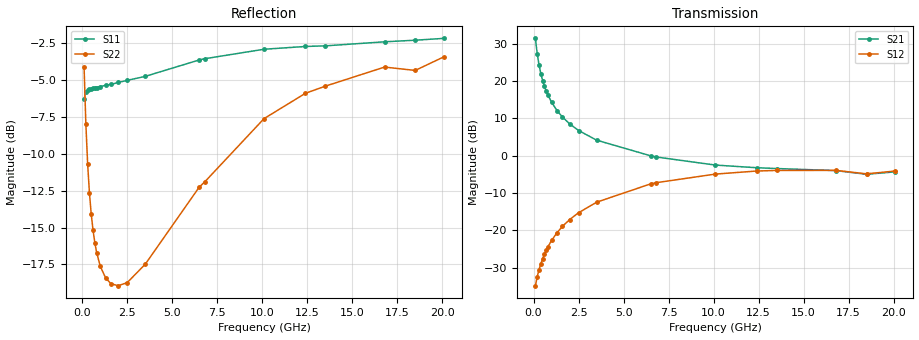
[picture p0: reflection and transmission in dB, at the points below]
!  Infineon Technologies AG
! BFR380L3 , PF131585-7, No.6, Th 09.10.01, soldered on pcb-board, measured with PP GSG850
!  Vce=5.0 V,  Ic=75.0 mA
! Common Emitter S-Parameters:  15. November 2001
#  GHz  S  MA  R  50
! f  S11  S21  S12  S22
! GHz  Mag  Ang  Mag  Ang  Mag  Ang  Mag  Ang
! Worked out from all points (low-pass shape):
!   201 points, 100 MHz to 20.1 GHz, reference 50 ohm
!   highest |S21| = 31.42 dB at 100 MHz (marker M1); lowest = -5.0 dB at 18.5 GHz (marker M2)
!   |S21| within 3 dB of the highest: start of sweep to 173.1 MHz
!   lowest |S11| = -6.3 dB at 100 MHz (marker M3), VSWR 2.89, Z = 28.2 - j35.6 ohm
!   |S11| at or under -10 dB: nowhere
!   |S22| runs from -18.9 to -3.4 dB; largest |S21 - S12| = 37
!   S11 on the Smith chart (normalised r, x): 100 MHz: 0.56, -0.71; 400 MHz: 0.32, -0.16; 2.5 GHz: 0.30, +0.25; 6.5 GHz: 0.33, +0.75; 12.4 GHz: 0.54, +1.51; 20.1 GHz: 1.07, +2.57
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0.1  0.4856 -97.0  37.25 132.8  0.01825 58.7  0.6247 -42.4
0.2  0.5121 -134.1  23.22 112.9  0.02407 56.5  0.3992 -57.9
0.3  0.5205 -150.4  16.39 103.6  0.02993 58.8  0.2912 -63.2
0.4  0.5239 -159.8  12.57 97.8  0.03571 61.5  0.2325 -65.4
0.5  0.5267 -166.3  10.16 93.7  0.04159 64.1  0.197 -66.5
0.6  0.5283 -171.0  8.52 90.4  0.04801 65.9  0.174 -67.1
0.7  0.5301 -174.8  7.344 87.6  0.05417 67.0  0.1577 -67.7
0.8  0.5308 -178.1  6.446 85.1  0.06071 68.2  0.1462 -68.4
1  0.5349 176.4  5.193 80.8  0.07372 69.4  0.1314 -70.2
1.3  0.54 169.9  4.028 75.1  0.0934 69.7  0.1199 -74.3
1.6  0.544 164.2  3.302 69.9  0.1134 69.2  0.1146 -79.7
2  0.5521 157.3  2.673 63.6  0.1399 67.9  0.1129 -87.8
2.5  0.5614 149.8  2.178 56.2  0.173 65.6  0.1157 -99.4
3.5  0.5791 135.8  1.618 42.7  0.2391 59.7  0.1335 -121.6
6.5  0.6583 102.4  0.9988 12.3  0.4202 39.3  0.2438 179.7
6.8  0.6646 99.5  0.964 9.9  0.4358 36.9  0.2538 175.0
10.1  0.7157 74.6  0.7508 -8.9  0.5684 13.8  0.4163 134.8
12.4  0.7314 62.5  0.6915 -18.2  0.625 -1.4  0.5073 111.8
13.5  0.7349 57.5  0.6751 -22.4  0.636 -8.2  0.5363 103.0
16.8  0.7586 46.1  0.633 -32.9  0.6376 -24.8  0.6227 79.6
18.5  0.7681 44.2  0.5647 -39.9  0.5727 -33.1  0.6066 73.6
20.1  0.7792 37.4  0.6098 -43.5  0.6257 -38.7  0.6747 62.3
